VERSION 5.5 ;
NAMESCASESENSITIVE ON ;
BUSBITCHARS "[]" ;
DIVIDERCHAR "/" ;

PROPERTYDEFINITIONS
  LAYER routingPitch REAL ;
END PROPERTYDEFINITIONS

UNITS
  DATABASE MICRONS 1000 ;
END UNITS
MANUFACTURINGGRID 0.01 ;
LAYER POLY1
  TYPE MASTERSLICE ;
END POLY1

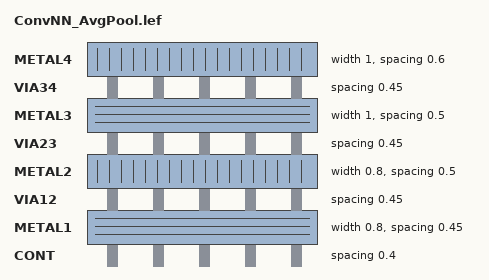
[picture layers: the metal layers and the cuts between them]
LAYER CONT
  TYPE CUT ;
  SPACING 0.4 ;
END CONT

LAYER METAL1
  TYPE ROUTING ;
  DIRECTION HORIZONTAL ;
  PITCH 0 ;
  WIDTH 0.8 ;
  SPACING 0.45 ;
  PROPERTY routingPitch 1.25 ;
END METAL1

LAYER VIA12
  TYPE CUT ;
  SPACING 0.45 ;
END VIA12

LAYER METAL2
  TYPE ROUTING ;
  DIRECTION VERTICAL ;
  PITCH 0 ;
  WIDTH 0.8 ;
  SPACING 0.5 ;
  PROPERTY routingPitch 1.4 ;
END METAL2

LAYER VIA23
  TYPE CUT ;
  SPACING 0.45 ;
END VIA23

LAYER METAL3
  TYPE ROUTING ;
  DIRECTION HORIZONTAL ;
  PITCH 0 ;
  WIDTH 1.0 ;
  SPACING 0.5 ;
  PROPERTY routingPitch 1.25 ;
END METAL3

LAYER VIA34
  TYPE CUT ;
  SPACING 0.45 ;
END VIA34

LAYER METAL4
  TYPE ROUTING ;
  DIRECTION VERTICAL ;
  PITCH 0 ;
  WIDTH 1.0 ;
  SPACING 0.6 ;
  PROPERTY routingPitch 1.4 ;
END METAL4

LAYER OVERLAP
  TYPE OVERLAP ;
END OVERLAP

VIARULE M4_M3 GENERATE
  LAYER METAL3 ;
    ENCLOSURE 0.2 0.2 ;
  LAYER METAL4 ;
    ENCLOSURE 0.15 0.15 ;
  LAYER VIA34 ;
    RECT -0.25 -0.25 0.25 0.25 ;
    SPACING 1 BY 1 ;
END M4_M3

VIARULE M3_M2 GENERATE
  LAYER METAL2 ;
    ENCLOSURE 0.2 0.2 ;
  LAYER METAL3 ;
    ENCLOSURE 0.15 0.15 ;
  LAYER VIA23 ;
    RECT -0.25 -0.25 0.25 0.25 ;
    SPACING 1 BY 1 ;
END M3_M2

VIARULE M2_M1 GENERATE
  LAYER METAL1 ;
    ENCLOSURE 0.2 0.2 ;
  LAYER METAL2 ;
    ENCLOSURE 0.15 0.15 ;
  LAYER VIA12 ;
    RECT -0.25 -0.25 0.25 0.25 ;
    SPACING 1 BY 1 ;
END M2_M1

VIARULE M1_POLY1 GENERATE
  LAYER POLY1 ;
    ENCLOSURE 0.2 0.2 ;
  LAYER METAL1 ;
    ENCLOSURE 0.15 0.15 ;
  LAYER CONT ;
    RECT -0.2 -0.2 0.2 0.2 ;
    SPACING 1 BY 1 ;
END M1_POLY1

VIA M1_POLY1
  LAYER CONT ;
    RECT -0.2 -0.2 0.2 0.2 ;
  LAYER POLY1 ;
    RECT -0.4 -0.4 0.4 0.4 ;
  LAYER METAL1 ;
    RECT -0.35 -0.35 0.35 0.35 ;
END M1_POLY1

VIA M2_M1
  LAYER VIA12 ;
    RECT -0.25 -0.25 0.25 0.25 ;
  LAYER METAL2 ;
    RECT -0.4 -0.4 0.4 0.4 ;
  LAYER METAL1 ;
    RECT -0.45 -0.45 0.45 0.45 ;
END M2_M1

VIA M3_M2
  LAYER VIA23 ;
    RECT -0.25 -0.25 0.25 0.25 ;
  LAYER METAL3 ;
    RECT -0.4 -0.4 0.4 0.4 ;
  LAYER METAL2 ;
    RECT -0.45 -0.45 0.45 0.45 ;
END M3_M2

VIA M4_M3
  LAYER VIA34 ;
    RECT -0.25 -0.25 0.25 0.25 ;
  LAYER METAL4 ;
    RECT -0.4 -0.4 0.4 0.4 ;
  LAYER METAL3 ;
    RECT -0.45 -0.45 0.45 0.45 ;
END M4_M3


MACRO TSMC350nm_VinjDecode2to4_vtile_spacing
END TSMC350nm_VinjDecode2to4_vtile_spacing

MACRO TSMC350nm_VinjDecode2to4_vtile_bridge_spacing
END TSMC350nm_VinjDecode2to4_vtile_bridge_spacing

MACRO TSMC350nm_VinjDecode2to4_vtile_D_bridge
END TSMC350nm_VinjDecode2to4_vtile_D_bridge

MACRO TSMC350nm_VinjDecode2to4_vtile
  PIN Vinj
    DIRECTION INOUT ;
    USE SIGNAL ;
    PORT
      LAYER METAL1 ;
        RECT 7.78 11.04 9.06 11.45 ;
    END
  END Vinj
  PIN OUT<0>
    DIRECTION INOUT ;
    USE SIGNAL ;
    PORT
      LAYER METAL1 ;
        RECT 19.66 18.91 20.11 19.59 ;
    END
  END OUT<0>
  PIN OUT<1>
    DIRECTION INOUT ;
    USE SIGNAL ;
    PORT
      LAYER METAL1 ;
        RECT 19.66 13.41 20.12 14.1 ;
    END
  END OUT<1>
  PIN OUT<2>
    DIRECTION INOUT ;
    USE SIGNAL ;
    PORT
      LAYER METAL1 ;
        RECT 19.66 7.92 20.11 8.59 ;
    END
  END OUT<2>
  PIN OUT<3>
    DIRECTION INOUT ;
    USE SIGNAL ;
    PORT
      LAYER METAL1 ;
        RECT 19.66 2.41 20.11 3.09 ;
    END
  END OUT<3>
  PIN ENABLE
    DIRECTION INOUT ;
    USE SIGNAL ;
    PORT
      LAYER METAL1 ;
        RECT 0.01 3.48 0.71 4.21 ;
    END
  END ENABLE
  PIN GND
    DIRECTION INOUT ;
    USE SIGNAL ;
    PORT
      LAYER METAL1 ;
        RECT 19.52 5.0 20.12 5.99 ;
    END
  END GND
  PIN VINJ
    DIRECTION INOUT ;
    USE SIGNAL ;
    PORT
      LAYER METAL1 ;
        RECT 19.15 21.56 20.05 21.96 ;
    END
  END VINJ
  PIN IN<1>
    DIRECTION INOUT ;
    USE SIGNAL ;
    PORT
      LAYER METAL2 ;
        RECT 6.56 20.89 7.5 22.0 ;
    END
  END IN<1>
  PIN IN<0>
    DIRECTION INOUT ;
    USE SIGNAL ;
    PORT
      LAYER METAL2 ;
        RECT 3.9 20.96 4.5 22.0 ;
    END
  END IN<0>
END TSMC350nm_VinjDecode2to4_vtile

MACRO TSMC350nm_VinjDecode2to4_vtile_C_bridge
END TSMC350nm_VinjDecode2to4_vtile_C_bridge

MACRO TSMC350nm_VinjDecode2to4_vtile_B_bridge
END TSMC350nm_VinjDecode2to4_vtile_B_bridge

MACRO TSMC350nm_VinjDecode2to4_vtile_A_bridge
END TSMC350nm_VinjDecode2to4_vtile_A_bridge

MACRO TSMC350nm_drainSelect_progrundrains
  PIN prog_drain<3>
    DIRECTION INOUT ;
    USE SIGNAL ;
    PORT
      LAYER METAL1 ;
        RECT 30.93 0.93 31.86 1.43 ;
    END
  END prog_drain<3>
  PIN prog_drain<2>
    DIRECTION INOUT ;
    USE SIGNAL ;
    PORT
      LAYER METAL1 ;
        RECT 30.97 9.62 31.86 10.12 ;
    END
  END prog_drain<2>
  PIN prog_drain<1>
    DIRECTION INOUT ;
    USE SIGNAL ;
    PORT
      LAYER METAL1 ;
        RECT 31.0 13.97 31.86 14.47 ;
    END
  END prog_drain<1>
  PIN run_drain<3>
    DIRECTION INOUT ;
    USE SIGNAL ;
    PORT
      LAYER METAL1 ;
        RECT 31.01 2.45 31.86 2.95 ;
    END
  END run_drain<3>
  PIN run_drain<2>
    DIRECTION INOUT ;
    USE SIGNAL ;
    PORT
      LAYER METAL1 ;
        RECT 30.94 5.31 31.86 5.81 ;
    END
  END run_drain<2>
  PIN prog_drain<0>
    DIRECTION INOUT ;
    USE SIGNAL ;
    PORT
      LAYER METAL1 ;
        RECT 31.12 20.75 31.86 21.25 ;
    END
  END prog_drain<0>
  PIN GND
    DIRECTION INOUT ;
    USE SIGNAL ;
    PORT
      LAYER METAL2 ;
        RECT 4.19 21.33 4.99 22.0 ;
    END
  END GND
  PIN VINJ
    DIRECTION INOUT ;
    USE SIGNAL ;
    PORT
      LAYER METAL1 ;
        RECT 1.4 21.5 2.8 22.0 ;
    END
  END VINJ
  PIN run_drain<0>
    DIRECTION INOUT ;
    USE SIGNAL ;
    PORT
      LAYER METAL1 ;
        RECT 31.01 19.56 31.86 20.06 ;
    END
  END run_drain<0>
  PIN run_drain<1>
    DIRECTION INOUT ;
    USE SIGNAL ;
    PORT
      LAYER METAL1 ;
        RECT 31.04 16.75 31.86 17.24 ;
    END
  END run_drain<1>
  PIN SELECT<3>
    DIRECTION INOUT ;
    USE SIGNAL ;
    PORT
      LAYER METAL1 ;
        RECT 0.0 2.54 0.67 2.97 ;
    END
  END SELECT<3>
  PIN SELET<2>
    DIRECTION INOUT ;
    USE SIGNAL ;
    PORT
      LAYER METAL1 ;
        RECT 0.0 8.03 0.67 8.46 ;
    END
  END SELET<2>
  PIN SELECT<1>
    DIRECTION INOUT ;
    USE SIGNAL ;
    PORT
      LAYER METAL1 ;
        RECT 0.0 13.54 0.67 13.97 ;
    END
  END SELECT<1>
  PIN SELECT<0>
    DIRECTION INOUT ;
    USE SIGNAL ;
    PORT
      LAYER METAL1 ;
        RECT 0.0 18.9 0.67 19.6 ;
    END
  END SELECT<0>
  PIN VINJ_b
    DIRECTION INOUT ;
    USE SIGNAL ;
    PORT
      LAYER METAL2 ;
        RECT 21.94 0.0 23.29 0.58 ;
    END
  END VINJ_b
  PIN GND_b
    DIRECTION INOUT ;
    USE SIGNAL ;
    PORT
      LAYER METAL2 ;
        RECT 17.16 0.0 18.16 0.58 ;
    END
  END GND_b
  PIN run_drainrail
    DIRECTION INOUT ;
    USE SIGNAL ;
    PORT
      LAYER METAL2 ;
        RECT 27.01 21.19 27.71 22.0 ;
    END
  END run_drainrail
  PIN prog_drainrail
    DIRECTION INOUT ;
    USE SIGNAL ;
    PORT
      LAYER METAL2 ;
        RECT 7.36 21.34 8.16 22.0 ;
    END
  END prog_drainrail
END TSMC350nm_drainSelect_progrundrains

MACRO TSMC350nm_4TGate_ST_draincutoff
  PIN In<0>
    DIRECTION INOUT ;
    USE SIGNAL ;
    PORT
      LAYER METAL1 ;
        RECT 9.96 17.5 10.6 18.45 ;
    END
  END In<0>
  PIN In<1>
    DIRECTION INOUT ;
    USE SIGNAL ;
    PORT
      LAYER METAL1 ;
        RECT 9.91 14.7 10.6 15.93 ;
    END
  END In<1>
  PIN In<2>
    DIRECTION INOUT ;
    USE SIGNAL ;
    PORT
      LAYER METAL1 ;
        RECT 10.01 6.9 10.6 7.8 ;
    END
  END In<2>
  PIN In<3>
    DIRECTION INOUT ;
    USE SIGNAL ;
    PORT
      LAYER METAL1 ;
        RECT 10.02 3.5 10.6 4.3 ;
    END
  END In<3>
  PIN A<0>
    DIRECTION INOUT ;
    USE SIGNAL ;
    PORT
      LAYER METAL1 ;
        RECT 0.0 19.56 1.4 20.06 ;
    END
  END A<0>
  PIN A<1>
    DIRECTION INOUT ;
    USE SIGNAL ;
    PORT
      LAYER METAL1 ;
        RECT 0.0 16.75 1.4 17.25 ;
    END
  END A<1>
  PIN A<2>
    DIRECTION INOUT ;
    USE SIGNAL ;
    PORT
      LAYER METAL1 ;
        RECT 0.0 5.3 1.4 5.8 ;
    END
  END A<2>
  PIN A<3>
    DIRECTION INOUT ;
    USE SIGNAL ;
    PORT
      LAYER METAL1 ;
        RECT 0.0 2.45 1.4 2.95 ;
    END
  END A<3>
  PIN P<0>
    DIRECTION INOUT ;
    USE SIGNAL ;
    PORT
      LAYER METAL1 ;
        RECT 0.0 20.75 1.4 21.25 ;
    END
  END P<0>
  PIN P<1>
    DIRECTION INOUT ;
    USE SIGNAL ;
    PORT
      LAYER METAL1 ;
        RECT 0.0 13.97 1.4 14.47 ;
    END
  END P<1>
  PIN P<2>
    DIRECTION INOUT ;
    USE SIGNAL ;
    PORT
      LAYER METAL1 ;
        RECT 0.0 9.62 1.4 10.12 ;
    END
  END P<2>
  PIN P<3>
    DIRECTION INOUT ;
    USE SIGNAL ;
    PORT
      LAYER METAL1 ;
        RECT 0.0 0.93 1.4 1.43 ;
    END
  END P<3>
  PIN PR<0>
    DIRECTION INOUT ;
    USE SIGNAL ;
    PORT
      LAYER METAL1 ;
        RECT 10.0 20.3 10.6 21.25 ;
    END
  END PR<0>
  PIN PR<1>
    DIRECTION INOUT ;
    USE SIGNAL ;
    PORT
      LAYER METAL1 ;
        RECT 10.13 11.9 10.6 12.8 ;
    END
  END PR<1>
  PIN PR<2>
    DIRECTION INOUT ;
    USE SIGNAL ;
    PORT
      LAYER METAL1 ;
        RECT 10.0 9.4 10.6 10.3 ;
    END
  END PR<2>
  PIN PR<3>
    DIRECTION INOUT ;
    USE SIGNAL ;
    PORT
      LAYER METAL1 ;
        RECT 10.0 0.7 10.6 1.6 ;
    END
  END PR<3>
  PIN VDD_b
    DIRECTION INOUT ;
    USE SIGNAL ;
    PORT
      LAYER METAL2 ;
        RECT 7.89 0.0 8.79 0.54 ;
    END
  END VDD_b
  PIN RUN
    DIRECTION INOUT ;
    USE SIGNAL ;
    PORT
      LAYER METAL2 ;
        RECT 5.9 21.13 6.5 22.0 ;
    END
  END RUN
  PIN VDD
    DIRECTION INOUT ;
    USE SIGNAL ;
    PORT
      LAYER METAL2 ;
        RECT 7.89 21.3 8.79 22.0 ;
    END
  END VDD
  PIN GND
    DIRECTION INOUT ;
    USE SIGNAL ;
    PORT
      LAYER METAL2 ;
        RECT 3.35 21.3 4.25 22.0 ;
    END
  END GND
  PIN GND_b
    DIRECTION INOUT ;
    USE SIGNAL ;
    PORT
      LAYER METAL2 ;
        RECT 3.35 0.0 4.25 0.73 ;
    END
  END GND_b
  PIN RUN_b
    DIRECTION INOUT ;
    USE SIGNAL ;
    PORT
      LAYER METAL2 ;
        RECT 5.9 0.0 6.5 0.71 ;
    END
  END RUN_b
END TSMC350nm_4TGate_ST_draincutoff

MACRO TSMC350nm_IndirectSwitches
  PIN GND_B<1>
    DIRECTION INOUT ;
    USE SIGNAL ;
    PORT
      LAYER METAL2 ;
        RECT 15.41 0.0 16.01 0.85 ;
    END
  END GND_B<1>
  PIN GND_B<0>
    DIRECTION INOUT ;
    USE SIGNAL ;
    PORT
      LAYER METAL2 ;
        RECT 11.2 0.0 11.8 0.85 ;
    END
  END GND_B<0>
  PIN GND
    DIRECTION INOUT ;
    USE SIGNAL ;
    PORT
      LAYER METAL2 ;
        RECT 11.2 3.21 11.8 3.6 ;
    END
  END GND
  PIN GND_T
    DIRECTION INOUT ;
    USE SIGNAL ;
    PORT
      LAYER METAL2 ;
        RECT 15.4 21.0 16.2 22.0 ;
    END
  END GND_T
  PIN VINJ_T
    DIRECTION INOUT ;
    USE SIGNAL ;
    PORT
      LAYER METAL2 ;
        RECT 6.3 21.04 7.32 22.0 ;
    END
  END VINJ_T
  PIN VDD<1>
    DIRECTION INOUT ;
    USE SIGNAL ;
    PORT
      LAYER METAL2 ;
        RECT 24.5 0.0 25.1 0.75 ;
    END
  END VDD<1>
  PIN VTUN
    DIRECTION INOUT ;
    USE SIGNAL ;
    PORT
      LAYER METAL2 ;
        RECT 13.3 0.0 13.9 0.82 ;
    END
  END VTUN
  PIN VINJ
    DIRECTION INOUT ;
    USE SIGNAL ;
    PORT
      LAYER METAL2 ;
        RECT 4.2 0.0 4.8 1.0 ;
    END
  END VINJ
  PIN VDD<0>
    DIRECTION INOUT ;
    USE SIGNAL ;
    PORT
      LAYER METAL2 ;
        RECT 2.1 0.0 2.7 1.09 ;
    END
  END VDD<0>
  PIN Vg<0>
    DIRECTION INOUT ;
    USE SIGNAL ;
    PORT
      LAYER METAL2 ;
        RECT 8.4 0.005 9.0 0.825 ;
    END
  END Vg<0>
  PIN CTRL_B<0>
    DIRECTION INOUT ;
    USE SIGNAL ;
    PORT
      LAYER METAL2 ;
        RECT 6.3 0.01 6.9 0.76 ;
    END
  END CTRL_B<0>
  PIN CTRL_B<1>
    DIRECTION INOUT ;
    USE SIGNAL ;
    PORT
      LAYER METAL2 ;
        RECT 20.3 0.01 20.9 0.75 ;
    END
  END CTRL_B<1>
  PIN Vg<1>
    DIRECTION INOUT ;
    USE SIGNAL ;
    PORT
      LAYER METAL2 ;
        RECT 18.2 0.0 18.8 0.76 ;
    END
  END Vg<1>
  PIN decode<0>
    DIRECTION INOUT ;
    USE SIGNAL ;
    PORT
      LAYER METAL2 ;
        RECT 3.46 21.16 4.8 22.0 ;
    END
  END decode<0>
  PIN RUN_IN<1>
    DIRECTION INOUT ;
    USE SIGNAL ;
    PORT
      LAYER METAL2 ;
        RECT 17.5 21.01 18.1 22.0 ;
    END
  END RUN_IN<1>
  PIN RUN_IN<0>
    DIRECTION INOUT ;
    USE SIGNAL ;
    PORT
      LAYER METAL2 ;
        RECT 10.5 20.9 11.1 22.0 ;
    END
  END RUN_IN<0>
  PIN VPWR<1>
    DIRECTION INOUT ;
    USE SIGNAL ;
    PORT
      LAYER METAL2 ;
        RECT 21.7 21.08 22.3 22.0 ;
    END
  END VPWR<1>
  PIN decode<1>
    DIRECTION INOUT ;
    USE SIGNAL ;
    PORT
      LAYER METAL2 ;
        RECT 23.8 21.09 25.0 22.0 ;
    END
  END decode<1>
  PIN VPWR<0>
    DIRECTION INOUT ;
    USE SIGNAL ;
    PORT
      LAYER METAL2 ;
        RECT 1.71 21.21 2.43 22.0 ;
    END
  END VPWR<0>
  PIN VTUN_T
    DIRECTION INOUT ;
    USE SIGNAL ;
    PORT
      LAYER METAL2 ;
        RECT 12.6 21.12 13.7 22.0 ;
    END
  END VTUN_T
  PIN vtun_r
    DIRECTION INOUT ;
    USE SIGNAL ;
    PORT
      LAYER METAL1 ;
        RECT 26.17 0.9 27.46 2.17 ;
    END
  END vtun_r
  PIN vgsel_r
    DIRECTION INOUT ;
    USE SIGNAL ;
    PORT
      LAYER METAL1 ;
        RECT 26.52 3.15 27.46 4.45 ;
    END
  END vgsel_r
  PIN prog_r
    DIRECTION INOUT ;
    USE SIGNAL ;
    PORT
      LAYER METAL1 ;
        RECT 26.59 9.15 27.46 10.55 ;
    END
  END prog_r
  PIN run_r
    DIRECTION INOUT ;
    USE SIGNAL ;
    PORT
      LAYER METAL1 ;
        RECT 26.28 6.05 27.46 7.29 ;
    END
  END run_r
  PIN RUN
    DIRECTION INOUT ;
    USE SIGNAL ;
    PORT
      LAYER METAL1 ;
        RECT 0.0 6.05 0.91 7.29 ;
    END
  END RUN
  PIN PROG
    DIRECTION INOUT ;
    USE SIGNAL ;
    PORT
      LAYER METAL1 ;
        RECT 0.0 9.15 0.87 10.55 ;
    END
  END PROG
  PIN Vgsel
    DIRECTION INOUT ;
    USE SIGNAL ;
    PORT
      LAYER METAL1 ;
        RECT 0.0 3.72 0.91 4.45 ;
    END
  END Vgsel
  PIN vtun_l
    DIRECTION INOUT ;
    USE SIGNAL ;
    PORT
      LAYER METAL1 ;
        RECT 0.0 0.9 1.31 1.88 ;
    END
  END vtun_l
END TSMC350nm_IndirectSwitches

MACRO TSMC350nm_VinjDecode2to4_htile
  PIN IN<1>
    DIRECTION INOUT ;
    USE SIGNAL ;
    PORT
      LAYER METAL1 ;
        RECT 0.0 11.85 0.9 12.74 ;
    END
  END IN<1>
  PIN IN<0>
    DIRECTION INOUT ;
    USE SIGNAL ;
    PORT
      LAYER METAL1 ;
        RECT 0.0 10.13 0.87 11.1 ;
    END
  END IN<0>
  PIN VINJ
    DIRECTION INOUT ;
    USE SIGNAL ;
    PORT
      LAYER METAL1 ;
        RECT 0.0 1.99 0.5 2.49 ;
    END
  END VINJ
  PIN GND
    DIRECTION INOUT ;
    USE SIGNAL ;
    PORT
      LAYER METAL1 ;
        RECT 0.0 6.99 0.51 7.49 ;
    END
  END GND
  PIN GND_b<1>
    DIRECTION INOUT ;
    USE SIGNAL ;
    PORT
      LAYER METAL2 ;
        RECT 40.32 0.0 40.92 1.79 ;
    END
  END GND_b<1>
  PIN VINJ_b<1>
    DIRECTION INOUT ;
    USE SIGNAL ;
    PORT
      LAYER METAL2 ;
        RECT 22.1 0.0 22.7 1.44 ;
    END
  END VINJ_b<1>
  PIN GND_b<0>
    DIRECTION INOUT ;
    USE SIGNAL ;
    PORT
      LAYER METAL2 ;
        RECT 18.85 0.0 19.45 1.41 ;
    END
  END GND_b<0>
  PIN VINJ_b<0>
    DIRECTION INOUT ;
    USE SIGNAL ;
    PORT
      LAYER METAL2 ;
        RECT 1.07 0.0 1.67 1.25 ;
    END
  END VINJ_b<0>
  PIN VINJV
    DIRECTION INOUT ;
    USE SIGNAL ;
    PORT
      LAYER METAL2 ;
        RECT 23.7 21.26 24.31 22.0 ;
    END
  END VINJV
  PIN GNDV
    DIRECTION INOUT ;
    USE SIGNAL ;
    PORT
      LAYER METAL2 ;
        RECT 25.84 21.28 26.44 22.0 ;
    END
  END GNDV
  PIN RUN_OUT<3>
    DIRECTION INOUT ;
    USE SIGNAL ;
    PORT
      LAYER METAL2 ;
        RECT 34.39 0.0 35.19 0.86 ;
    END
  END RUN_OUT<3>
  PIN RUN_OUT<2>
    DIRECTION INOUT ;
    USE SIGNAL ;
    PORT
      LAYER METAL2 ;
        RECT 28.77 0.0 29.57 0.86 ;
    END
  END RUN_OUT<2>
  PIN RUN_OUT<1>
    DIRECTION INOUT ;
    USE SIGNAL ;
    PORT
      LAYER METAL2 ;
        RECT 13.5 0.0 14.1 0.86 ;
    END
  END RUN_OUT<1>
  PIN RUN_OUT<0>
    DIRECTION INOUT ;
    USE SIGNAL ;
    PORT
      LAYER METAL2 ;
        RECT 7.34 0.0 8.14 0.86 ;
    END
  END RUN_OUT<0>
  PIN ENABLE
    DIRECTION INOUT ;
    USE SIGNAL ;
    PORT
      LAYER METAL2 ;
        RECT 6.29 21.66 6.89 22.0 ;
    END
  END ENABLE
  PIN OUT<2>
    DIRECTION INOUT ;
    USE SIGNAL ;
    PORT
      LAYER METAL2 ;
        RECT 25.28 0.0 25.87 0.87 ;
    END
  END OUT<2>
  PIN OUT<3>
    DIRECTION INOUT ;
    USE SIGNAL ;
    PORT
      LAYER METAL2 ;
        RECT 37.14 0.0 37.73 0.83 ;
    END
  END OUT<3>
  PIN OUT<0>
    DIRECTION INOUT ;
    USE SIGNAL ;
    PORT
      LAYER METAL2 ;
        RECT 4.27 0.0 4.87 0.86 ;
    END
  END OUT<0>
  PIN OUT<1>
    DIRECTION INOUT ;
    USE SIGNAL ;
    PORT
      LAYER METAL2 ;
        RECT 16.14 0.0 16.72 0.85 ;
    END
  END OUT<1>
  PIN VGRUN<0>
    DIRECTION INOUT ;
    USE SIGNAL ;
    PORT
      LAYER METAL2 ;
        RECT 9.1 21.59 9.7 22.0 ;
    END
  END VGRUN<0>
  PIN VGRUN<1>
    DIRECTION INOUT ;
    USE SIGNAL ;
    PORT
      LAYER METAL2 ;
        RECT 11.2 21.6 11.8 22.0 ;
    END
  END VGRUN<1>
  PIN VGRUN<2>
    DIRECTION INOUT ;
    USE SIGNAL ;
    PORT
      LAYER METAL2 ;
        RECT 28.7 21.71 29.3 22.0 ;
    END
  END VGRUN<2>
  PIN VGRUN<3>
    DIRECTION INOUT ;
    USE SIGNAL ;
    PORT
      LAYER METAL2 ;
        RECT 33.6 21.54 34.2 22.0 ;
    END
  END VGRUN<3>
END TSMC350nm_VinjDecode2to4_htile

MACRO TSMC350nm_VinjDecode2to4_htile_A_bridge
  PIN VGRUN<3>
    DIRECTION INOUT ;
    USE SIGNAL ;
    PORT
      LAYER METAL2 ;
        RECT 34.5 9.46 35.1 10.0 ;
    END
  END VGRUN<3>
  PIN VGRUN<2>
    DIRECTION INOUT ;
    USE SIGNAL ;
    PORT
      LAYER METAL2 ;
        RECT 26.6 9.56 27.2 10.0 ;
    END
  END VGRUN<2>
  PIN VGRUN<1>
    DIRECTION INOUT ;
    USE SIGNAL ;
    PORT
      LAYER METAL2 ;
        RECT 13.5 9.46 14.1 10.0 ;
    END
  END VGRUN<1>
  PIN VGRUN<0>
    DIRECTION INOUT ;
    USE SIGNAL ;
    PORT
      LAYER METAL2 ;
        RECT 5.6 9.52 6.2 10.0 ;
    END
  END VGRUN<0>
END TSMC350nm_VinjDecode2to4_htile_A_bridge

MACRO TSMC350nm_VinjDecode2to4_htile_B_bridge
  PIN VGRUN<0>
    DIRECTION INOUT ;
    USE SIGNAL ;
    PORT
      LAYER METAL2 ;
        RECT 9.1 9.52 9.7 10.0 ;
    END
  END VGRUN<0>
  PIN VGRUN<1>
    DIRECTION INOUT ;
    USE SIGNAL ;
    PORT
      LAYER METAL2 ;
        RECT 11.2 9.52 11.8 10.0 ;
    END
  END VGRUN<1>
  PIN VGRUN<2>
    DIRECTION INOUT ;
    USE SIGNAL ;
    PORT
      LAYER METAL2 ;
        RECT 28.7 9.5 29.3 10.0 ;
    END
  END VGRUN<2>
  PIN VGRUN<3>
    DIRECTION INOUT ;
    USE SIGNAL ;
    PORT
      LAYER METAL2 ;
        RECT 33.6 9.51 34.2 10.0 ;
    END
  END VGRUN<3>
END TSMC350nm_VinjDecode2to4_htile_B_bridge

MACRO TSMC350nm_VinjDecode2to4_htile_C_bridge
  PIN VGRUN<0>
    DIRECTION INOUT ;
    USE SIGNAL ;
    PORT
      LAYER METAL2 ;
        RECT 9.1 9.54 9.7 10.0 ;
    END
  END VGRUN<0>
  PIN VGRUN<1>
    DIRECTION INOUT ;
    USE SIGNAL ;
    PORT
      LAYER METAL2 ;
        RECT 11.2 9.57 11.8 10.0 ;
    END
  END VGRUN<1>
  PIN VGRUN<2>
    DIRECTION INOUT ;
    USE SIGNAL ;
    PORT
      LAYER METAL2 ;
        RECT 28.7 9.59 29.3 10.0 ;
    END
  END VGRUN<2>
  PIN VGRUN<3>
    DIRECTION INOUT ;
    USE SIGNAL ;
    PORT
      LAYER METAL2 ;
        RECT 33.6 9.57 34.2 10.0 ;
    END
  END VGRUN<3>
END TSMC350nm_VinjDecode2to4_htile_C_bridge

MACRO TSMC350nm_VinjDecode2to4_htile_spacing
  PIN VGRUN<0>
    DIRECTION INOUT ;
    USE SIGNAL ;
    PORT
      LAYER METAL2 ;
        RECT 9.1 21.59 9.7 22.0 ;
    END
  END VGRUN<0>
  PIN VGRUN<1>
    DIRECTION INOUT ;
    USE SIGNAL ;
    PORT
      LAYER METAL2 ;
        RECT 11.2 21.52 11.8 22.0 ;
    END
  END VGRUN<1>
  PIN VGRUN<2>
    DIRECTION INOUT ;
    USE SIGNAL ;
    PORT
      LAYER METAL2 ;
        RECT 28.7 21.54 29.3 22.0 ;
    END
  END VGRUN<2>
  PIN VGRUN<3>
    DIRECTION INOUT ;
    USE SIGNAL ;
    PORT
      LAYER METAL2 ;
        RECT 33.6 21.55 34.2 22.0 ;
    END
  END VGRUN<3>
END TSMC350nm_VinjDecode2to4_htile_spacing

MACRO Tgate_swc_fr_Kernel_Vert
  PIN Vimg
    DIRECTION INOUT ;
    USE SIGNAL ;
    PORT
      LAYER METAL1 ;
        RECT 0.0 17.02 0.39 17.72 ;
    END
  END Vimg
  PIN AVDD
    DIRECTION INOUT ;
    USE SIGNAL ;
    PORT
      LAYER METAL1 ;
        RECT 0.0 14.02 0.39 15.02 ;
    END
  END AVDD
  PIN DVDD
    DIRECTION INOUT ;
    USE SIGNAL ;
    PORT
      LAYER METAL1 ;
        RECT 0.0 9.47 0.39 10.47 ;
    END
  END DVDD
  PIN GND
    DIRECTION INOUT ;
    USE SIGNAL ;
    PORT
      LAYER METAL2 ;
        RECT 4.39 21.77 5.19 22.0 ;
    END
  END GND
  PIN Q_bot
    DIRECTION INOUT ;
    USE SIGNAL ;
    PORT
      LAYER METAL2 ;
        RECT 6.57 0.0 7.35 0.35 ;
    END
  END Q_bot
  PIN Vg_R
    DIRECTION INOUT ;
    USE SIGNAL ;
    PORT
      LAYER METAL2 ;
        RECT 1.25 0.0 2.05 0.35 ;
    END
  END Vg_R
  PIN Q
    DIRECTION INOUT ;
    USE SIGNAL ;
    PORT
      LAYER METAL2 ;
        RECT 8.6 21.77 9.2 22.0 ;
    END
  END Q
END Tgate_swc_fr_Kernel_Vert

MACRO DynamicShiftReg_Rst_Lo
  PIN Q
    DIRECTION INOUT ;
    USE SIGNAL ;
    PORT
      LAYER METAL1 ;
        RECT 10.73 19.48 11.13 20.18 ;
    END
  END Q
  PIN GND
    DIRECTION INOUT ;
    USE SIGNAL ;
    PORT
      LAYER METAL1 ;
        RECT 0.0 0.5 0.4 1.3 ;
    END
  END GND
  PIN Din
    DIRECTION INOUT ;
    USE SIGNAL ;
    PORT
      LAYER METAL1 ;
        RECT 0.0 19.48 0.4 20.18 ;
    END
  END Din
  PIN RST
    DIRECTION INOUT ;
    USE SIGNAL ;
    PORT
      LAYER METAL1 ;
        RECT 0.0 10.56 0.4 11.26 ;
    END
  END RST
  PIN DVDD
    DIRECTION INOUT ;
    USE SIGNAL ;
    PORT
      LAYER METAL1 ;
        RECT 0.0 13.07 0.4 13.77 ;
    END
  END DVDD
  PIN CLK
    DIRECTION INOUT ;
    USE SIGNAL ;
    PORT
      LAYER METAL1 ;
        RECT 0.0 9.15 0.4 9.85 ;
    END
  END CLK
  PIN CLKB
    DIRECTION INOUT ;
    USE SIGNAL ;
    PORT
      LAYER METAL1 ;
        RECT 0.0 7.92 0.4 8.62 ;
    END
  END CLKB
END DynamicShiftReg_Rst_Lo

MACRO Integration_fr_AvgPool_core
  PIN GND
    DIRECTION INOUT ;
    USE SIGNAL ;
    PORT
      LAYER METAL1 ;
        RECT 71.84 21.51 73.23 22.0 ;
    END
  END GND
  PIN Q
    DIRECTION INOUT ;
    USE SIGNAL ;
    PORT
      LAYER METAL3 ;
        RECT 0.0 6.24 0.6 7.04 ;
    END
  END Q
  PIN Vd_run
    DIRECTION INOUT ;
    USE SIGNAL ;
    PORT
      LAYER METAL2 ;
        RECT 0.0 16.45 0.37 17.25 ;
    END
  END Vd_run
  PIN Vd_prog
    DIRECTION INOUT ;
    USE SIGNAL ;
    PORT
      LAYER METAL2 ;
        RECT 0.0 20.43 0.37 21.23 ;
    END
  END Vd_prog
  PIN int_rst
    DIRECTION INOUT ;
    USE SIGNAL ;
    PORT
      LAYER METAL2 ;
        RECT 0.0 13.45 0.37 14.25 ;
    END
  END int_rst
  PIN Vint
    DIRECTION INOUT ;
    USE SIGNAL ;
    PORT
      LAYER METAL2 ;
        RECT 0.0 14.95 0.37 15.75 ;
    END
  END Vint
  PIN DVDD
    DIRECTION INOUT ;
    USE SIGNAL ;
    PORT
      LAYER METAL2 ;
        RECT 0.0 11.95 0.37 12.75 ;
    END
  END DVDD
  PIN Din
    DIRECTION INOUT ;
    USE SIGNAL ;
    PORT
      LAYER METAL3 ;
        RECT 0.0 2.15 0.6 2.95 ;
    END
  END Din
  PIN RST_B
    DIRECTION INOUT ;
    USE SIGNAL ;
    PORT
      LAYER METAL1 ;
        RECT 14.55 21.51 15.35 22.0 ;
    END
  END RST_B
  PIN CLK
    DIRECTION INOUT ;
    USE SIGNAL ;
    PORT
      LAYER METAL1 ;
        RECT 13.14 21.51 14.1 22.0 ;
    END
  END CLK
  PIN Vimg_CLK
    DIRECTION INOUT ;
    USE SIGNAL ;
    PORT
      LAYER METAL1 ;
        RECT 27.28 21.51 28.28 22.0 ;
    END
  END Vimg_CLK
  PIN CLKB
    DIRECTION INOUT ;
    USE SIGNAL ;
    PORT
      LAYER METAL1 ;
        RECT 11.61 21.51 12.61 22.0 ;
    END
  END CLKB
  PIN nxt_row<1>
    DIRECTION INOUT ;
    USE SIGNAL ;
    PORT
      LAYER METAL1 ;
        RECT 290.26 21.52 291.26 22.0 ;
    END
  END nxt_row<1>
  PIN AVDD_by_2<1>
    DIRECTION INOUT ;
    USE SIGNAL ;
    PORT
      LAYER METAL1 ;
        RECT 197.65 21.52 198.65 22.0 ;
    END
  END AVDD_by_2<1>
  PIN prog<1>
    DIRECTION INOUT ;
    USE SIGNAL ;
    PORT
      LAYER METAL1 ;
        RECT 195.23 21.52 196.23 22.0 ;
    END
  END prog<1>
  PIN run<1>
    DIRECTION INOUT ;
    USE SIGNAL ;
    PORT
      LAYER METAL1 ;
        RECT 192.83 21.52 193.83 22.0 ;
    END
  END run<1>
  PIN Vg<1>
    DIRECTION INOUT ;
    USE SIGNAL ;
    PORT
      LAYER METAL1 ;
        RECT 190.43 21.52 191.43 22.0 ;
    END
  END Vg<1>
  PIN Vsel_b<1>
    DIRECTION INOUT ;
    USE SIGNAL ;
    PORT
      LAYER METAL1 ;
        RECT 187.93 21.51 188.93 22.0 ;
    END
  END Vsel_b<1>
  PIN AVDD<1>
    DIRECTION INOUT ;
    USE SIGNAL ;
    PORT
      LAYER METAL1 ;
        RECT 185.43 21.51 186.43 22.0 ;
    END
  END AVDD<1>
  PIN VINJ<1>
    DIRECTION INOUT ;
    USE SIGNAL ;
    PORT
      LAYER METAL1 ;
        RECT 176.82 21.51 177.82 22.0 ;
    END
  END VINJ<1>
  PIN VTUN
    DIRECTION INOUT ;
    USE SIGNAL ;
    PORT
      LAYER METAL1 ;
        RECT 167.86 21.51 168.86 22.0 ;
    END
  END VTUN
  PIN VINJ<0>
    DIRECTION INOUT ;
    USE SIGNAL ;
    PORT
      LAYER METAL1 ;
        RECT 158.92 21.51 159.92 22.0 ;
    END
  END VINJ<0>
  PIN AVDD<0>
    DIRECTION INOUT ;
    USE SIGNAL ;
    PORT
      LAYER METAL1 ;
        RECT 150.82 21.51 151.82 22.0 ;
    END
  END AVDD<0>
  PIN Vsel_b<0>
    DIRECTION INOUT ;
    USE SIGNAL ;
    PORT
      LAYER METAL1 ;
        RECT 148.32 21.51 149.32 22.0 ;
    END
  END Vsel_b<0>
  PIN Vg<0>
    DIRECTION INOUT ;
    USE SIGNAL ;
    PORT
      LAYER METAL1 ;
        RECT 145.82 21.51 146.82 22.0 ;
    END
  END Vg<0>
  PIN run<0>
    DIRECTION INOUT ;
    USE SIGNAL ;
    PORT
      LAYER METAL1 ;
        RECT 143.42 21.51 144.42 22.0 ;
    END
  END run<0>
  PIN prog<0>
    DIRECTION INOUT ;
    USE SIGNAL ;
    PORT
      LAYER METAL1 ;
        RECT 141.02 21.51 142.02 22.0 ;
    END
  END prog<0>
  PIN AVDD_by_2<0>
    DIRECTION INOUT ;
    USE SIGNAL ;
    PORT
      LAYER METAL1 ;
        RECT 138.6 21.51 139.6 22.0 ;
    END
  END AVDD_by_2<0>
  PIN nxt_row<0>
    DIRECTION INOUT ;
    USE SIGNAL ;
    PORT
      LAYER METAL1 ;
        RECT 45.99 21.51 46.99 22.0 ;
    END
  END nxt_row<0>
END Integration_fr_AvgPool_core

MACRO I_Subtractor_AvgPool_core
  PIN Vd_prog_0_in
    DIRECTION INOUT ;
    USE SIGNAL ;
    PORT
      LAYER METAL2 ;
        RECT 0.0 18.88 0.37 19.88 ;
    END
  END Vd_prog_0_in
  PIN Vd_prog_0_out
    DIRECTION INOUT ;
    USE SIGNAL ;
    PORT
      LAYER METAL2 ;
        RECT 38.54 20.43 38.91 21.23 ;
    END
  END Vd_prog_0_out
  PIN Vd_run_krnl
    DIRECTION INOUT ;
    USE SIGNAL ;
    PORT
      LAYER METAL2 ;
        RECT 0.0 5.66 0.37 6.66 ;
    END
  END Vd_run_krnl
  PIN Vd_run_avg_pool
    DIRECTION INOUT ;
    USE SIGNAL ;
    PORT
      LAYER METAL2 ;
        RECT 38.54 16.45 38.91 17.25 ;
    END
  END Vd_run_avg_pool
  PIN Vint_out
    DIRECTION INOUT ;
    USE SIGNAL ;
    PORT
      LAYER METAL2 ;
        RECT 38.54 14.95 38.91 15.75 ;
    END
  END Vint_out
  PIN DVDD
    DIRECTION INOUT ;
    USE SIGNAL ;
    PORT
      LAYER METAL1 ;
        RECT 31.8 21.54 32.8 22.0 ;
    END
  END DVDD
  PIN GND
    DIRECTION INOUT ;
    USE SIGNAL ;
    PORT
      LAYER METAL1 ;
        RECT 12.02 21.54 17.24 22.0 ;
    END
  END GND
  PIN Vint_in
    DIRECTION INOUT ;
    USE SIGNAL ;
    PORT
      LAYER METAL2 ;
        RECT 0.0 16.27 0.37 17.27 ;
    END
  END Vint_in
  PIN run_lv
    DIRECTION INOUT ;
    USE SIGNAL ;
    PORT
      LAYER METAL1 ;
        RECT 36.65 21.54 37.65 22.0 ;
    END
  END run_lv
  PIN prog_lv
    DIRECTION INOUT ;
    USE SIGNAL ;
    PORT
      LAYER METAL1 ;
        RECT 29.8 21.54 30.8 22.0 ;
    END
  END prog_lv
END I_Subtractor_AvgPool_core

MACRO Tgate_swc_fr_Kernel_Horiz_top_edge
  PIN Q
    DIRECTION INOUT ;
    USE SIGNAL ;
    PORT
      LAYER METAL1 ;
        RECT 10.73 19.48 11.13 20.18 ;
    END
  END Q
  PIN GND
    DIRECTION INOUT ;
    USE SIGNAL ;
    PORT
      LAYER METAL1 ;
        RECT 30.84 21.37 31.64 22.0 ;
    END
  END GND
  PIN Din
    DIRECTION INOUT ;
    USE SIGNAL ;
    PORT
      LAYER METAL1 ;
        RECT 49.82 21.37 50.52 22.0 ;
    END
  END Din
  PIN RST
    DIRECTION INOUT ;
    USE SIGNAL ;
    PORT
      LAYER METAL1 ;
        RECT 0.0 10.56 0.4 11.26 ;
    END
  END RST
  PIN DVDD
    DIRECTION INOUT ;
    USE SIGNAL ;
    PORT
      LAYER METAL1 ;
        RECT 43.41 21.37 44.11 22.0 ;
    END
  END DVDD
  PIN CLK
    DIRECTION INOUT ;
    USE SIGNAL ;
    PORT
      LAYER METAL1 ;
        RECT 39.49 21.37 40.19 22.0 ;
    END
  END CLK
  PIN CLKB
    DIRECTION INOUT ;
    USE SIGNAL ;
    PORT
      LAYER METAL1 ;
        RECT 38.26 21.37 38.96 22.0 ;
    END
  END CLKB
  PIN Final_row_out
    DIRECTION INOUT ;
    USE SIGNAL ;
    PORT
      LAYER METAL1 ;
        RECT 52.52 21.4 53.32 22.0 ;
    END
  END Final_row_out
  PIN I_m
    DIRECTION INOUT ;
    USE SIGNAL ;
    PORT
      LAYER METAL2 ;
        RECT 53.79 12.7 54.46 13.7 ;
    END
  END I_m
  PIN I_p
    DIRECTION INOUT ;
    USE SIGNAL ;
    PORT
      LAYER METAL2 ;
        RECT 53.79 16.27 54.46 17.27 ;
    END
  END I_p
  PIN Vd<0>
    DIRECTION INOUT ;
    USE SIGNAL ;
    PORT
      LAYER METAL1 ;
        RECT 0.0 17.5 0.42 18.2 ;
    END
  END Vd<0>
  PIN RUN_HV
    DIRECTION INOUT ;
    USE SIGNAL ;
    PORT
      LAYER METAL2 ;
        RECT 23.12 21.33 23.92 22.0 ;
    END
  END RUN_HV
  PIN VINJ
    DIRECTION INOUT ;
    USE SIGNAL ;
    PORT
      LAYER METAL2 ;
        RECT 9.08 21.33 10.08 22.0 ;
    END
  END VINJ
  PIN Vd_prog_0_out
    DIRECTION INOUT ;
    USE SIGNAL ;
    PORT
      LAYER METAL2 ;
        RECT 53.79 18.87 54.46 19.87 ;
    END
  END Vd_prog_0_out
  PIN Final_row_in
    DIRECTION INOUT ;
    USE SIGNAL ;
    PORT
      LAYER METAL1 ;
        RECT 52.52 0.0 53.32 0.6 ;
    END
  END Final_row_in
  PIN Vd_prog_0_in
    DIRECTION INOUT ;
    USE SIGNAL ;
    PORT
      LAYER METAL1 ;
        RECT 0.0 20.3 0.41 20.8 ;
    END
  END Vd_prog_0_in
  PIN Q<1>
    DIRECTION INOUT ;
    USE SIGNAL ;
    PORT
      LAYER METAL1 ;
        RECT 49.82 0.0 50.52 0.63 ;
    END
  END Q<1>
  PIN RSTB
    DIRECTION INOUT ;
    USE SIGNAL ;
    PORT
      LAYER METAL1 ;
        RECT 40.9 21.37 41.6 22.0 ;
    END
  END RSTB
  PIN Vd<3>
    DIRECTION INOUT ;
    USE SIGNAL ;
    PORT
      LAYER METAL1 ;
        RECT 0.0 3.3 0.42 4.0 ;
    END
  END Vd<3>
  PIN Vd<2>
    DIRECTION INOUT ;
    USE SIGNAL ;
    PORT
      LAYER METAL1 ;
        RECT 0.0 6.33 0.42 7.03 ;
    END
  END Vd<2>
  PIN Vd<1>
    DIRECTION INOUT ;
    USE SIGNAL ;
    PORT
      LAYER METAL1 ;
        RECT 0.0 14.5 0.42 15.2 ;
    END
  END Vd<1>
END Tgate_swc_fr_Kernel_Horiz_top_edge

MACRO Tgate_swc_fr_Kernel_Horiz_bot_edge
  PIN Q
    DIRECTION INOUT ;
    USE SIGNAL ;
    PORT
      LAYER METAL2 ;
        RECT 30.34 1.93 30.62 2.53 ;
    END
  END Q
  PIN GND
    DIRECTION INOUT ;
    USE SIGNAL ;
    PORT
      LAYER METAL1 ;
        RECT 30.84 21.37 31.64 22.0 ;
    END
  END GND
  PIN Final_row_out
    DIRECTION INOUT ;
    USE SIGNAL ;
    PORT
      LAYER METAL1 ;
        RECT 52.52 21.4 53.32 22.0 ;
    END
  END Final_row_out
  PIN I_m
    DIRECTION INOUT ;
    USE SIGNAL ;
    PORT
      LAYER METAL2 ;
        RECT 53.79 12.7 54.46 13.7 ;
    END
  END I_m
  PIN I_p
    DIRECTION INOUT ;
    USE SIGNAL ;
    PORT
      LAYER METAL2 ;
        RECT 53.79 16.27 54.46 17.27 ;
    END
  END I_p
  PIN Vd<0>
    DIRECTION INOUT ;
    USE SIGNAL ;
    PORT
      LAYER METAL1 ;
        RECT 0.0 17.5 0.42 18.2 ;
    END
  END Vd<0>
  PIN RUN_HV
    DIRECTION INOUT ;
    USE SIGNAL ;
    PORT
      LAYER METAL2 ;
        RECT 23.12 21.33 23.92 22.0 ;
    END
  END RUN_HV
  PIN VINJ
    DIRECTION INOUT ;
    USE SIGNAL ;
    PORT
      LAYER METAL2 ;
        RECT 9.08 21.33 10.08 22.0 ;
    END
  END VINJ
  PIN Vd_prog_0_out
    DIRECTION INOUT ;
    USE SIGNAL ;
    PORT
      LAYER METAL2 ;
        RECT 53.79 18.87 54.46 19.87 ;
    END
  END Vd_prog_0_out
  PIN Final_row_in
    DIRECTION INOUT ;
    USE SIGNAL ;
    PORT
      LAYER METAL1 ;
        RECT 52.52 0.86 53.32 1.46 ;
    END
  END Final_row_in
  PIN Vd_prog_0_in
    DIRECTION INOUT ;
    USE SIGNAL ;
    PORT
      LAYER METAL1 ;
        RECT 0.0 20.3 0.41 20.8 ;
    END
  END Vd_prog_0_in
  PIN DVDD
    DIRECTION INOUT ;
    USE SIGNAL ;
    PORT
      LAYER METAL1 ;
        RECT 43.41 21.37 44.11 22.0 ;
    END
  END DVDD
  PIN RSTB
    DIRECTION INOUT ;
    USE SIGNAL ;
    PORT
      LAYER METAL1 ;
        RECT 40.9 21.37 41.6 22.0 ;
    END
  END RSTB
  PIN CLK
    DIRECTION INOUT ;
    USE SIGNAL ;
    PORT
      LAYER METAL1 ;
        RECT 39.49 21.37 40.19 22.0 ;
    END
  END CLK
  PIN CLKB
    DIRECTION INOUT ;
    USE SIGNAL ;
    PORT
      LAYER METAL1 ;
        RECT 38.26 21.37 38.96 22.0 ;
    END
  END CLKB
  PIN Din
    DIRECTION INOUT ;
    USE SIGNAL ;
    PORT
      LAYER METAL1 ;
        RECT 49.82 21.37 50.52 22.0 ;
    END
  END Din
  PIN Vd<3>
    DIRECTION INOUT ;
    USE SIGNAL ;
    PORT
      LAYER METAL1 ;
        RECT 0.0 3.3 0.42 4.0 ;
    END
  END Vd<3>
  PIN Vd<2>
    DIRECTION INOUT ;
    USE SIGNAL ;
    PORT
      LAYER METAL1 ;
        RECT 0.0 6.33 0.42 7.03 ;
    END
  END Vd<2>
  PIN Vd<1>
    DIRECTION INOUT ;
    USE SIGNAL ;
    PORT
      LAYER METAL1 ;
        RECT 0.0 14.5 0.42 15.2 ;
    END
  END Vd<1>
END Tgate_swc_fr_Kernel_Horiz_bot_edge

MACRO AvgPool_n_Relu
  PIN DVDD
    DIRECTION INOUT ;
    USE SIGNAL ;
    PORT
      LAYER METAL2 ;
        RECT 94.23 9.83 94.6 10.63 ;
    END
  END DVDD
  PIN DVDD_l
    DIRECTION INOUT ;
    USE SIGNAL ;
    PORT
      LAYER METAL2 ;
        RECT 0.0 11.95 0.37 12.75 ;
    END
  END DVDD_l
  PIN Sub_img_out
    DIRECTION INOUT ;
    USE SIGNAL ;
    PORT
      LAYER METAL2 ;
        RECT 94.23 7.23 94.6 8.43 ;
    END
  END Sub_img_out
  PIN Out_En_b
    DIRECTION INOUT ;
    USE SIGNAL ;
    PORT
      LAYER METAL2 ;
        RECT 94.23 5.03 94.6 5.83 ;
    END
  END Out_En_b
  PIN Vd_prog_out
    DIRECTION INOUT ;
    USE SIGNAL ;
    PORT
      LAYER METAL2 ;
        RECT 94.23 19.8 94.6 20.6 ;
    END
  END Vd_prog_out
  PIN int_rst_out
    DIRECTION INOUT ;
    USE SIGNAL ;
    PORT
      LAYER METAL2 ;
        RECT 94.23 12.03 94.6 12.83 ;
    END
  END int_rst_out
  PIN Vint_out
    DIRECTION INOUT ;
    USE SIGNAL ;
    PORT
      LAYER METAL2 ;
        RECT 94.23 14.95 94.6 15.75 ;
    END
  END Vint_out
  PIN Q_out
    DIRECTION INOUT ;
    USE SIGNAL ;
    PORT
      LAYER METAL2 ;
        RECT 94.23 2.83 94.6 3.63 ;
    END
  END Q_out
  PIN GND
    DIRECTION INOUT ;
    USE SIGNAL ;
    PORT
      LAYER METAL2 ;
        RECT 94.23 17.15 94.6 18.35 ;
    END
  END GND
  PIN Q_in
    DIRECTION INOUT ;
    USE SIGNAL ;
    PORT
      LAYER METAL2 ;
        RECT 0.0 2.15 0.37 2.95 ;
    END
  END Q_in
  PIN Vint_in
    DIRECTION INOUT ;
    USE SIGNAL ;
    PORT
      LAYER METAL2 ;
        RECT 0.0 14.95 0.37 15.75 ;
    END
  END Vint_in
  PIN int_rst_in
    DIRECTION INOUT ;
    USE SIGNAL ;
    PORT
      LAYER METAL2 ;
        RECT 0.0 13.45 0.37 14.25 ;
    END
  END int_rst_in
  PIN Vd_prog_in
    DIRECTION INOUT ;
    USE SIGNAL ;
    PORT
      LAYER METAL2 ;
        RECT 0.0 20.43 0.37 21.23 ;
    END
  END Vd_prog_in
  PIN Vd_run
    DIRECTION INOUT ;
    USE SIGNAL ;
    PORT
      LAYER METAL2 ;
        RECT 0.0 16.45 0.37 17.25 ;
    END
  END Vd_run
  PIN AVDD
    DIRECTION INOUT ;
    USE SIGNAL ;
    PORT
      LAYER METAL1 ;
        RECT 80.32 21.53 81.32 22.0 ;
    END
  END AVDD
  PIN Vb
    DIRECTION INOUT ;
    USE SIGNAL ;
    PORT
      LAYER METAL1 ;
        RECT 52.1 21.53 53.1 22.0 ;
    END
  END Vb
  PIN run_lv
    DIRECTION INOUT ;
    USE SIGNAL ;
    PORT
      LAYER METAL1 ;
        RECT 8.03 21.53 9.03 22.0 ;
    END
  END run_lv
  PIN prog_lv
    DIRECTION INOUT ;
    USE SIGNAL ;
    PORT
      LAYER METAL1 ;
        RECT 5.63 21.53 6.63 22.0 ;
    END
  END prog_lv
END AvgPool_n_Relu

MACRO tile_analog_frame
  PIN n_Kvmm_G_En
    DIRECTION INOUT ;
    USE SIGNAL ;
    PORT
      LAYER METAL3 ;
        RECT 13.3 1702.21 14.7 1705.01 ;
    END
  END n_Kvmm_G_En
  PIN n_AvgPool_FGs_G_En
    DIRECTION INOUT ;
    USE SIGNAL ;
    PORT
      LAYER METAL3 ;
        RECT 27.3 1702.21 28.7 1705.01 ;
    END
  END n_AvgPool_FGs_G_En
  PIN n_Kvmm_G_bit<0>
    DIRECTION INOUT ;
    USE SIGNAL ;
    PORT
      LAYER METAL3 ;
        RECT 41.3 1702.21 42.7 1705.01 ;
    END
  END n_Kvmm_G_bit<0>
  PIN n_Kvmm_G_bit<1>
    DIRECTION INOUT ;
    USE SIGNAL ;
    PORT
      LAYER METAL3 ;
        RECT 55.3 1702.21 56.7 1705.01 ;
    END
  END n_Kvmm_G_bit<1>
  PIN n_Kvmm_G_bit<2>
    DIRECTION INOUT ;
    USE SIGNAL ;
    PORT
      LAYER METAL3 ;
        RECT 69.3 1702.21 70.7 1705.01 ;
    END
  END n_Kvmm_G_bit<2>
  PIN n_Kvmm_G_bit<3>
    DIRECTION INOUT ;
    USE SIGNAL ;
    PORT
      LAYER METAL3 ;
        RECT 83.3 1702.21 84.7 1705.01 ;
    END
  END n_Kvmm_G_bit<3>
  PIN n_Kvmm_AvgP_Dr_En
    DIRECTION INOUT ;
    USE SIGNAL ;
    PORT
      LAYER METAL3 ;
        RECT 97.3 1702.21 98.7 1705.01 ;
    END
  END n_Kvmm_AvgP_Dr_En
  PIN n_Kvmm_AvgP_Dr_bit<0>
    DIRECTION INOUT ;
    USE SIGNAL ;
    PORT
      LAYER METAL3 ;
        RECT 111.3 1702.21 112.7 1705.01 ;
    END
  END n_Kvmm_AvgP_Dr_bit<0>
  PIN n_Kvmm_AvgP_Dr_bit<1>
    DIRECTION INOUT ;
    USE SIGNAL ;
    PORT
      LAYER METAL3 ;
        RECT 125.3 1702.21 126.7 1705.01 ;
    END
  END n_Kvmm_AvgP_Dr_bit<1>
  PIN n_Kvmm_AvgP_Dr_bit<2>
    DIRECTION INOUT ;
    USE SIGNAL ;
    PORT
      LAYER METAL3 ;
        RECT 139.3 1702.21 140.7 1705.01 ;
    END
  END n_Kvmm_AvgP_Dr_bit<2>
  PIN n_Kvmm_AvgP_Dr_bit<3>
    DIRECTION INOUT ;
    USE SIGNAL ;
    PORT
      LAYER METAL3 ;
        RECT 153.3 1702.21 154.7 1705.01 ;
    END
  END n_Kvmm_AvgP_Dr_bit<3>
  PIN n_Kvmm_AvgP_Dr_bit<4>
    DIRECTION INOUT ;
    USE SIGNAL ;
    PORT
      LAYER METAL3 ;
        RECT 167.3 1702.21 168.7 1705.01 ;
    END
  END n_Kvmm_AvgP_Dr_bit<4>
  PIN n_Kvmm_AvgP_Dr_bit<5>
    DIRECTION INOUT ;
    USE SIGNAL ;
    PORT
      LAYER METAL3 ;
        RECT 181.3 1702.21 182.7 1705.01 ;
    END
  END n_Kvmm_AvgP_Dr_bit<5>
  PIN n_Kvmm_AvgP_Dr_bit<6>
    DIRECTION INOUT ;
    USE SIGNAL ;
    PORT
      LAYER METAL3 ;
        RECT 195.3 1702.21 196.7 1705.01 ;
    END
  END n_Kvmm_AvgP_Dr_bit<6>
  PIN n_Kvmm_AvgP_Dr_bit<7>
    DIRECTION INOUT ;
    USE SIGNAL ;
    PORT
      LAYER METAL3 ;
        RECT 209.3 1702.21 210.7 1705.01 ;
    END
  END n_Kvmm_AvgP_Dr_bit<7>
  PIN n_Kvmm_AvgP_Dr_bit<8>
    DIRECTION INOUT ;
    USE SIGNAL ;
    PORT
      LAYER METAL3 ;
        RECT 223.3 1702.21 224.7 1705.01 ;
    END
  END n_Kvmm_AvgP_Dr_bit<8>
  PIN n_Kvmm_AvgP_Prog_Drln
    DIRECTION INOUT ;
    USE SIGNAL ;
    PORT
      LAYER METAL3 ;
        RECT 237.3 1702.21 238.7 1705.01 ;
    END
  END n_Kvmm_AvgP_Prog_Drln
  PIN n_Kvmm_AvgP_Run_Drln
    DIRECTION INOUT ;
    USE SIGNAL ;
    PORT
      LAYER METAL3 ;
        RECT 251.3 1702.21 252.7 1705.01 ;
    END
  END n_Kvmm_AvgP_Run_Drln
  PIN n_K_col_Din
    DIRECTION INOUT ;
    USE SIGNAL ;
    PORT
      LAYER METAL3 ;
        RECT 265.3 1702.21 266.7 1705.01 ;
    END
  END n_K_col_Din
  PIN n_K_col_CLKB
    DIRECTION INOUT ;
    USE SIGNAL ;
    PORT
      LAYER METAL3 ;
        RECT 279.3 1702.21 280.7 1705.01 ;
    END
  END n_K_col_CLKB
  PIN n_K_col_RST_B
    DIRECTION INOUT ;
    USE SIGNAL ;
    PORT
      LAYER METAL3 ;
        RECT 293.3 1702.21 294.7 1705.01 ;
    END
  END n_K_col_RST_B
  PIN n_K_col_CLK
    DIRECTION INOUT ;
    USE SIGNAL ;
    PORT
      LAYER METAL3 ;
        RECT 307.3 1702.21 308.7 1705.01 ;
    END
  END n_K_col_CLK
  PIN n_AVDD_by_2
    DIRECTION INOUT ;
    USE SIGNAL ;
    PORT
      LAYER METAL3 ;
        RECT 321.3 1702.21 322.7 1705.01 ;
    END
  END n_AVDD_by_2
  PIN n_SR_Intg_RST_B
    DIRECTION INOUT ;
    USE SIGNAL ;
    PORT
      LAYER METAL3 ;
        RECT 335.3 1702.21 336.7 1705.01 ;
    END
  END n_SR_Intg_RST_B
  PIN n_SR_Intg_Din
    DIRECTION INOUT ;
    USE SIGNAL ;
    PORT
      LAYER METAL3 ;
        RECT 349.3 1702.21 350.7 1705.01 ;
    END
  END n_SR_Intg_Din
  PIN n_SR_Intg_CLK
    DIRECTION INOUT ;
    USE SIGNAL ;
    PORT
      LAYER METAL3 ;
        RECT 363.3 1702.21 364.7 1705.01 ;
    END
  END n_SR_Intg_CLK
  PIN n_SR_Intg_CLKB
    DIRECTION INOUT ;
    USE SIGNAL ;
    PORT
      LAYER METAL3 ;
        RECT 377.3 1702.21 378.7 1705.01 ;
    END
  END n_SR_Intg_CLKB
  PIN n_SR_Intg_nxt_rw
    DIRECTION INOUT ;
    USE SIGNAL ;
    PORT
      LAYER METAL3 ;
        RECT 391.3 1702.21 392.7 1705.01 ;
    END
  END n_SR_Intg_nxt_rw
  PIN n_Vimg_CLK
    DIRECTION INOUT ;
    USE SIGNAL ;
    PORT
      LAYER METAL3 ;
        RECT 405.3 1702.21 406.7 1705.01 ;
    END
  END n_Vimg_CLK
  PIN n_K_rw_Din
    DIRECTION INOUT ;
    USE SIGNAL ;
    PORT
      LAYER METAL3 ;
        RECT 419.3 1702.21 420.7 1705.01 ;
    END
  END n_K_rw_Din
  PIN n_K_rw_CLKB
    DIRECTION INOUT ;
    USE SIGNAL ;
    PORT
      LAYER METAL3 ;
        RECT 433.3 1702.21 434.7 1705.01 ;
    END
  END n_K_rw_CLKB
  PIN n_K_rw_RST_B
    DIRECTION INOUT ;
    USE SIGNAL ;
    PORT
      LAYER METAL3 ;
        RECT 447.3 1702.21 448.7 1705.01 ;
    END
  END n_K_rw_RST_B
  PIN n_K_rw_CLK
    DIRECTION INOUT ;
    USE SIGNAL ;
    PORT
      LAYER METAL3 ;
        RECT 461.3 1702.21 462.7 1705.01 ;
    END
  END n_K_rw_CLK
  PIN n_AvgPool_Relu_Vb
    DIRECTION INOUT ;
    USE SIGNAL ;
    PORT
      LAYER METAL3 ;
        RECT 475.3 1702.21 476.7 1705.01 ;
    END
  END n_AvgPool_Relu_Vb
  PIN n_VTUN
    DIRECTION INOUT ;
    USE SIGNAL ;
    PORT
      LAYER METAL3 ;
        RECT 489.3 1702.21 490.7 1705.01 ;
    END
  END n_VTUN
  PIN n_DVDD
    DIRECTION INOUT ;
    USE SIGNAL ;
    PORT
      LAYER METAL3 ;
        RECT 503.3 1702.21 504.7 1705.01 ;
    END
  END n_DVDD
  PIN n_AVDD
    DIRECTION INOUT ;
    USE SIGNAL ;
    PORT
      LAYER METAL3 ;
        RECT 517.3 1702.21 518.7 1705.01 ;
    END
  END n_AVDD
  PIN n_GND
    DIRECTION INOUT ;
    USE SIGNAL ;
    PORT
      LAYER METAL3 ;
        RECT 531.3 1702.21 532.7 1705.01 ;
    END
  END n_GND
  PIN n_VINJ
    DIRECTION INOUT ;
    USE SIGNAL ;
    PORT
      LAYER METAL3 ;
        RECT 545.3 1702.21 546.7 1705.01 ;
    END
  END n_VINJ
  PIN n_VGPROG
    DIRECTION INOUT ;
    USE SIGNAL ;
    PORT
      LAYER METAL3 ;
        RECT 559.3 1702.21 560.7 1705.01 ;
    END
  END n_VGPROG
  PIN n_prog_hv
    DIRECTION INOUT ;
    USE SIGNAL ;
    PORT
      LAYER METAL3 ;
        RECT 573.3 1702.21 574.7 1705.01 ;
    END
  END n_prog_hv
  PIN n_run_hv
    DIRECTION INOUT ;
    USE SIGNAL ;
    PORT
      LAYER METAL3 ;
        RECT 587.3 1702.21 588.7 1705.01 ;
    END
  END n_run_hv
  PIN n_prog_lv
    DIRECTION INOUT ;
    USE SIGNAL ;
    PORT
      LAYER METAL3 ;
        RECT 601.3 1702.21 602.7 1705.01 ;
    END
  END n_prog_lv
  PIN n_run_lv
    DIRECTION INOUT ;
    USE SIGNAL ;
    PORT
      LAYER METAL3 ;
        RECT 615.3 1702.21 616.7 1705.01 ;
    END
  END n_run_lv
  PIN e_Vin_inp_Ch<0>
    DIRECTION INOUT ;
    USE SIGNAL ;
    PORT
      LAYER METAL3 ;
        RECT 1812.51 1689.61 1815.31 1691.01 ;
    END
  END e_Vin_inp_Ch<0>
  PIN e_Vin_inp_Ch<1>
    DIRECTION INOUT ;
    USE SIGNAL ;
    PORT
      LAYER METAL3 ;
        RECT 1812.51 1675.61 1815.31 1677.01 ;
    END
  END e_Vin_inp_Ch<1>
  PIN e_Vin_inp_Ch<2>
    DIRECTION INOUT ;
    USE SIGNAL ;
    PORT
      LAYER METAL3 ;
        RECT 1812.51 1661.61 1815.31 1663.01 ;
    END
  END e_Vin_inp_Ch<2>
  PIN e_Sub_img_out<0>
    DIRECTION INOUT ;
    USE SIGNAL ;
    PORT
      LAYER METAL3 ;
        RECT 1812.51 1647.61 1815.31 1649.01 ;
    END
  END e_Sub_img_out<0>
  PIN e_Sub_img_out<1>
    DIRECTION INOUT ;
    USE SIGNAL ;
    PORT
      LAYER METAL3 ;
        RECT 1812.51 1633.61 1815.31 1635.01 ;
    END
  END e_Sub_img_out<1>
  PIN e_Sub_img_out<2>
    DIRECTION INOUT ;
    USE SIGNAL ;
    PORT
      LAYER METAL3 ;
        RECT 1812.51 1619.61 1815.31 1621.01 ;
    END
  END e_Sub_img_out<2>
  PIN e_Sub_img_out<3>
    DIRECTION INOUT ;
    USE SIGNAL ;
    PORT
      LAYER METAL3 ;
        RECT 1812.51 1605.61 1815.31 1607.01 ;
    END
  END e_Sub_img_out<3>
  PIN e_Sub_img_out<4>
    DIRECTION INOUT ;
    USE SIGNAL ;
    PORT
      LAYER METAL3 ;
        RECT 1812.51 1591.61 1815.31 1593.01 ;
    END
  END e_Sub_img_out<4>
  PIN e_Sub_img_out<5>
    DIRECTION INOUT ;
    USE SIGNAL ;
    PORT
      LAYER METAL3 ;
        RECT 1812.51 1577.61 1815.31 1579.01 ;
    END
  END e_Sub_img_out<5>
  PIN e_Sub_img_out<6>
    DIRECTION INOUT ;
    USE SIGNAL ;
    PORT
      LAYER METAL3 ;
        RECT 1812.51 1563.61 1815.31 1565.01 ;
    END
  END e_Sub_img_out<6>
  PIN e_Sub_img_out<7>
    DIRECTION INOUT ;
    USE SIGNAL ;
    PORT
      LAYER METAL3 ;
        RECT 1812.51 1549.61 1815.31 1551.01 ;
    END
  END e_Sub_img_out<7>
  PIN e_Sub_img_out<8>
    DIRECTION INOUT ;
    USE SIGNAL ;
    PORT
      LAYER METAL3 ;
        RECT 1812.51 1535.61 1815.31 1537.01 ;
    END
  END e_Sub_img_out<8>
  PIN e_Sub_img_out<9>
    DIRECTION INOUT ;
    USE SIGNAL ;
    PORT
      LAYER METAL3 ;
        RECT 1812.51 1521.61 1815.31 1523.01 ;
    END
  END e_Sub_img_out<9>
  PIN e_Sub_img_out<10>
    DIRECTION INOUT ;
    USE SIGNAL ;
    PORT
      LAYER METAL3 ;
        RECT 1812.51 1507.61 1815.31 1509.01 ;
    END
  END e_Sub_img_out<10>
  PIN e_Sub_img_out<11>
    DIRECTION INOUT ;
    USE SIGNAL ;
    PORT
      LAYER METAL3 ;
        RECT 1812.51 1493.61 1815.31 1495.01 ;
    END
  END e_Sub_img_out<11>
  PIN e_Sub_img_out<12>
    DIRECTION INOUT ;
    USE SIGNAL ;
    PORT
      LAYER METAL3 ;
        RECT 1812.51 1479.61 1815.31 1481.01 ;
    END
  END e_Sub_img_out<12>
  PIN e_Sub_img_out<13>
    DIRECTION INOUT ;
    USE SIGNAL ;
    PORT
      LAYER METAL3 ;
        RECT 1812.51 1465.61 1815.31 1467.01 ;
    END
  END e_Sub_img_out<13>
  PIN e_Sub_img_out<14>
    DIRECTION INOUT ;
    USE SIGNAL ;
    PORT
      LAYER METAL3 ;
        RECT 1812.51 1451.61 1815.31 1453.01 ;
    END
  END e_Sub_img_out<14>
  PIN e_Sub_img_out<15>
    DIRECTION INOUT ;
    USE SIGNAL ;
    PORT
      LAYER METAL3 ;
        RECT 1812.51 1437.61 1815.31 1439.01 ;
    END
  END e_Sub_img_out<15>
  PIN e_Sub_img_out<16>
    DIRECTION INOUT ;
    USE SIGNAL ;
    PORT
      LAYER METAL3 ;
        RECT 1812.51 1423.61 1815.31 1425.01 ;
    END
  END e_Sub_img_out<16>
  PIN e_Sub_img_out<17>
    DIRECTION INOUT ;
    USE SIGNAL ;
    PORT
      LAYER METAL3 ;
        RECT 1812.51 1409.61 1815.31 1411.01 ;
    END
  END e_Sub_img_out<17>
  PIN e_Sub_img_out<18>
    DIRECTION INOUT ;
    USE SIGNAL ;
    PORT
      LAYER METAL3 ;
        RECT 1812.51 1395.61 1815.31 1397.01 ;
    END
  END e_Sub_img_out<18>
  PIN e_Sub_img_out<19>
    DIRECTION INOUT ;
    USE SIGNAL ;
    PORT
      LAYER METAL3 ;
        RECT 1812.51 1381.61 1815.31 1383.01 ;
    END
  END e_Sub_img_out<19>
  PIN e_Sub_img_out<20>
    DIRECTION INOUT ;
    USE SIGNAL ;
    PORT
      LAYER METAL3 ;
        RECT 1812.51 1367.61 1815.31 1369.01 ;
    END
  END e_Sub_img_out<20>
  PIN e_Sub_img_out<21>
    DIRECTION INOUT ;
    USE SIGNAL ;
    PORT
      LAYER METAL3 ;
        RECT 1812.51 1353.61 1815.31 1355.01 ;
    END
  END e_Sub_img_out<21>
  PIN e_Sub_img_out<22>
    DIRECTION INOUT ;
    USE SIGNAL ;
    PORT
      LAYER METAL3 ;
        RECT 1812.51 1339.61 1815.31 1341.01 ;
    END
  END e_Sub_img_out<22>
  PIN e_Sub_img_out<23>
    DIRECTION INOUT ;
    USE SIGNAL ;
    PORT
      LAYER METAL3 ;
        RECT 1812.51 1325.61 1815.31 1327.01 ;
    END
  END e_Sub_img_out<23>
  PIN e_Sub_img_out<24>
    DIRECTION INOUT ;
    USE SIGNAL ;
    PORT
      LAYER METAL3 ;
        RECT 1812.51 1311.61 1815.31 1313.01 ;
    END
  END e_Sub_img_out<24>
  PIN e_Sub_img_out<25>
    DIRECTION INOUT ;
    USE SIGNAL ;
    PORT
      LAYER METAL3 ;
        RECT 1812.51 1297.61 1815.31 1299.01 ;
    END
  END e_Sub_img_out<25>
  PIN e_Sub_img_out<26>
    DIRECTION INOUT ;
    USE SIGNAL ;
    PORT
      LAYER METAL3 ;
        RECT 1812.51 1283.61 1815.31 1285.01 ;
    END
  END e_Sub_img_out<26>
  PIN e_Sub_img_out<27>
    DIRECTION INOUT ;
    USE SIGNAL ;
    PORT
      LAYER METAL3 ;
        RECT 1812.51 1269.61 1815.31 1271.01 ;
    END
  END e_Sub_img_out<27>
  PIN e_Sub_img_out<28>
    DIRECTION INOUT ;
    USE SIGNAL ;
    PORT
      LAYER METAL3 ;
        RECT 1812.51 1255.61 1815.31 1257.01 ;
    END
  END e_Sub_img_out<28>
  PIN e_Sub_img_out<29>
    DIRECTION INOUT ;
    USE SIGNAL ;
    PORT
      LAYER METAL3 ;
        RECT 1812.51 1241.61 1815.31 1243.01 ;
    END
  END e_Sub_img_out<29>
  PIN e_Sub_img_out<30>
    DIRECTION INOUT ;
    USE SIGNAL ;
    PORT
      LAYER METAL3 ;
        RECT 1812.51 1227.61 1815.31 1229.01 ;
    END
  END e_Sub_img_out<30>
  PIN e_Sub_img_out<31>
    DIRECTION INOUT ;
    USE SIGNAL ;
    PORT
      LAYER METAL3 ;
        RECT 1812.51 1213.61 1815.31 1215.01 ;
    END
  END e_Sub_img_out<31>
  PIN e_Sub_img_out<32>
    DIRECTION INOUT ;
    USE SIGNAL ;
    PORT
      LAYER METAL3 ;
        RECT 1812.51 1199.61 1815.31 1201.01 ;
    END
  END e_Sub_img_out<32>
  PIN e_Sub_img_out<33>
    DIRECTION INOUT ;
    USE SIGNAL ;
    PORT
      LAYER METAL3 ;
        RECT 1812.51 1185.61 1815.31 1187.01 ;
    END
  END e_Sub_img_out<33>
END tile_analog_frame

MACRO TSMC350nm_4x2_Indirect
  PIN Vg<1>
    DIRECTION INOUT ;
    USE SIGNAL ;
    PORT
      LAYER METAL2 ;
        RECT 18.2 21.06 18.8 22.0 ;
    END
  END Vg<1>
  PIN Vsel<1>
    DIRECTION INOUT ;
    USE SIGNAL ;
    PORT
      LAYER METAL2 ;
        RECT 20.3 21.08 20.9 22.0 ;
    END
  END Vsel<1>
  PIN VINJ<1>
    DIRECTION INOUT ;
    USE SIGNAL ;
    PORT
      LAYER METAL2 ;
        RECT 22.4 21.05 23.0 22.0 ;
    END
  END VINJ<1>
  PIN Vsel<0>
    DIRECTION INOUT ;
    USE SIGNAL ;
    PORT
      LAYER METAL2 ;
        RECT 6.3 21.2 6.9 22.0 ;
    END
  END Vsel<0>
  PIN Vs<0>
    DIRECTION INOUT ;
    USE SIGNAL ;
    PORT
      LAYER METAL2 ;
        RECT 2.1 21.21 2.7 22.0 ;
    END
  END Vs<0>
  PIN Vs<1>
    DIRECTION INOUT ;
    USE SIGNAL ;
    PORT
      LAYER METAL2 ;
        RECT 24.5 21.06 25.1 22.0 ;
    END
  END Vs<1>
  PIN VTUN
    DIRECTION INOUT ;
    USE SIGNAL ;
    PORT
      LAYER METAL2 ;
        RECT 13.3 21.09 13.9 22.0 ;
    END
  END VTUN
  PIN VINJ<0>
    DIRECTION INOUT ;
    USE SIGNAL ;
    PORT
      LAYER METAL2 ;
        RECT 4.2 21.18 4.8 22.0 ;
    END
  END VINJ<0>
  PIN GND<0>
    DIRECTION INOUT ;
    USE SIGNAL ;
    PORT
      LAYER METAL2 ;
        RECT 11.2 21.07 11.8 22.0 ;
    END
  END GND<0>
  PIN Vg<0>
    DIRECTION INOUT ;
    USE SIGNAL ;
    PORT
      LAYER METAL2 ;
        RECT 8.4 21.03 9.0 22.0 ;
    END
  END Vg<0>
  PIN GND<1>
    DIRECTION INOUT ;
    USE SIGNAL ;
    PORT
      LAYER METAL2 ;
        RECT 15.41 21.06 16.01 22.0 ;
    END
  END GND<1>
  PIN Vs_b<0>
    DIRECTION INOUT ;
    USE SIGNAL ;
    PORT
      LAYER METAL2 ;
        RECT 1.42 0.0 2.7 0.6 ;
    END
  END Vs_b<0>
  PIN VINJ_b<0>
    DIRECTION INOUT ;
    USE SIGNAL ;
    PORT
      LAYER METAL2 ;
        RECT 4.2 0.0 4.8 0.76 ;
    END
  END VINJ_b<0>
  PIN Vsel_b<0>
    DIRECTION INOUT ;
    USE SIGNAL ;
    PORT
      LAYER METAL2 ;
        RECT 6.3 0.0 6.9 0.78 ;
    END
  END Vsel_b<0>
  PIN Vg_b<0>
    DIRECTION INOUT ;
    USE SIGNAL ;
    PORT
      LAYER METAL2 ;
        RECT 8.4 0.0 9.0 0.77 ;
    END
  END Vg_b<0>
  PIN GND_b<0>
    DIRECTION INOUT ;
    USE SIGNAL ;
    PORT
      LAYER METAL2 ;
        RECT 11.2 0.0 11.8 0.76 ;
    END
  END GND_b<0>
  PIN VTUN_b
    DIRECTION INOUT ;
    USE SIGNAL ;
    PORT
      LAYER METAL2 ;
        RECT 13.3 0.0 13.9 0.76 ;
    END
  END VTUN_b
  PIN GND_b<1>
    DIRECTION INOUT ;
    USE SIGNAL ;
    PORT
      LAYER METAL2 ;
        RECT 15.41 0.0 16.01 0.83 ;
    END
  END GND_b<1>
  PIN Vg_b<1>
    DIRECTION INOUT ;
    USE SIGNAL ;
    PORT
      LAYER METAL2 ;
        RECT 18.2 0.0 18.8 0.76 ;
    END
  END Vg_b<1>
  PIN Vsel_b<1>
    DIRECTION INOUT ;
    USE SIGNAL ;
    PORT
      LAYER METAL2 ;
        RECT 20.3 0.0 20.9 0.75 ;
    END
  END Vsel_b<1>
  PIN VINJ_b<1>
    DIRECTION INOUT ;
    USE SIGNAL ;
    PORT
      LAYER METAL2 ;
        RECT 22.4 0.0 23.0 0.77 ;
    END
  END VINJ_b<1>
  PIN Vs_b<1>
    DIRECTION INOUT ;
    USE SIGNAL ;
    PORT
      LAYER METAL2 ;
        RECT 24.5 0.0 25.75 0.61 ;
    END
  END Vs_b<1>
  PIN Vd_Pl<3>
    DIRECTION INOUT ;
    USE SIGNAL ;
    PORT
      LAYER METAL1 ;
        RECT 0.0 0.7 1.47 1.2 ;
    END
  END Vd_Pl<3>
  PIN Vd_Rl<3>
    DIRECTION INOUT ;
    USE SIGNAL ;
    PORT
      LAYER METAL1 ;
        RECT 0.0 3.5 1.45 4.0 ;
    END
  END Vd_Rl<3>
  PIN Vd_Rl<2>
    DIRECTION INOUT ;
    USE SIGNAL ;
    PORT
      LAYER METAL1 ;
        RECT 0.0 7.0 1.4 7.5 ;
    END
  END Vd_Rl<2>
  PIN Vd_Pl<2>
    DIRECTION INOUT ;
    USE SIGNAL ;
    PORT
      LAYER METAL1 ;
        RECT 0.0 9.8 1.41 10.3 ;
    END
  END Vd_Pl<2>
  PIN Vd_Pl<1>
    DIRECTION INOUT ;
    USE SIGNAL ;
    PORT
      LAYER METAL1 ;
        RECT 0.0 11.89 1.43 12.4 ;
    END
  END Vd_Pl<1>
  PIN Vd_Rl<1>
    DIRECTION INOUT ;
    USE SIGNAL ;
    PORT
      LAYER METAL1 ;
        RECT 0.0 14.7 1.46 15.2 ;
    END
  END Vd_Rl<1>
  PIN Vd_Rl<0>
    DIRECTION INOUT ;
    USE SIGNAL ;
    PORT
      LAYER METAL1 ;
        RECT 0.0 17.5 1.43 18.0 ;
    END
  END Vd_Rl<0>
  PIN Vd_Pl<0>
    DIRECTION INOUT ;
    USE SIGNAL ;
    PORT
      LAYER METAL1 ;
        RECT 0.0 20.3 1.4 20.9 ;
    END
  END Vd_Pl<0>
  PIN Vd_P<0>
    DIRECTION INOUT ;
    USE SIGNAL ;
    PORT
      LAYER METAL1 ;
        RECT 26.63 20.3 27.46 20.8 ;
    END
  END Vd_P<0>
  PIN Vd_R<1>
    DIRECTION INOUT ;
    USE SIGNAL ;
    PORT
      LAYER METAL1 ;
        RECT 26.56 14.7 27.44 15.2 ;
    END
  END Vd_R<1>
  PIN Vd_R<3>
    DIRECTION INOUT ;
    USE SIGNAL ;
    PORT
      LAYER METAL1 ;
        RECT 26.5 3.5 27.46 4.0 ;
    END
  END Vd_R<3>
  PIN Vd_P<3>
    DIRECTION INOUT ;
    USE SIGNAL ;
    PORT
      LAYER METAL1 ;
        RECT 26.55 0.7 27.46 1.2 ;
    END
  END Vd_P<3>
  PIN Vd_P<1>
    DIRECTION INOUT ;
    USE SIGNAL ;
    PORT
      LAYER METAL1 ;
        RECT 26.38 11.9 27.46 12.4 ;
    END
  END Vd_P<1>
  PIN Vd_P<2>
    DIRECTION INOUT ;
    USE SIGNAL ;
    PORT
      LAYER METAL1 ;
        RECT 26.51 9.8 27.46 10.3 ;
    END
  END Vd_P<2>
  PIN Vd_R<0>
    DIRECTION INOUT ;
    USE SIGNAL ;
    PORT
      LAYER METAL1 ;
        RECT 26.66 17.5 27.46 18.0 ;
    END
  END Vd_R<0>
  PIN Vd_R<2>
    DIRECTION INOUT ;
    USE SIGNAL ;
    PORT
      LAYER METAL1 ;
        RECT 26.53 7.0 27.46 7.5 ;
    END
  END Vd_R<2>
END TSMC350nm_4x2_Indirect

MACRO Integration_fr_AvgPool_start
  PIN GND
    DIRECTION INOUT ;
    USE SIGNAL ;
    PORT
      LAYER METAL1 ;
        RECT 71.84 21.51 73.23 22.0 ;
    END
  END GND
  PIN Q
    DIRECTION INOUT ;
    USE SIGNAL ;
    PORT
      LAYER METAL3 ;
        RECT 0.0 6.24 0.6 7.04 ;
    END
  END Q
  PIN Vd_run
    DIRECTION INOUT ;
    USE SIGNAL ;
    PORT
      LAYER METAL2 ;
        RECT 0.0 16.45 0.37 17.25 ;
    END
  END Vd_run
  PIN Vd_prog
    DIRECTION INOUT ;
    USE SIGNAL ;
    PORT
      LAYER METAL2 ;
        RECT 0.0 20.43 0.37 21.23 ;
    END
  END Vd_prog
  PIN int_rst
    DIRECTION INOUT ;
    USE SIGNAL ;
    PORT
      LAYER METAL2 ;
        RECT 0.0 13.45 0.37 14.25 ;
    END
  END int_rst
  PIN Vint
    DIRECTION INOUT ;
    USE SIGNAL ;
    PORT
      LAYER METAL2 ;
        RECT 0.0 14.95 0.37 15.75 ;
    END
  END Vint
  PIN DVDD
    DIRECTION INOUT ;
    USE SIGNAL ;
    PORT
      LAYER METAL2 ;
        RECT 0.0 11.95 0.37 12.75 ;
    END
  END DVDD
  PIN Din
    DIRECTION INOUT ;
    USE SIGNAL ;
    PORT
      LAYER METAL3 ;
        RECT 0.0 2.15 0.6 2.95 ;
    END
  END Din
  PIN RST_B
    DIRECTION INOUT ;
    USE SIGNAL ;
    PORT
      LAYER METAL1 ;
        RECT 14.55 21.51 15.35 22.0 ;
    END
  END RST_B
  PIN CLK
    DIRECTION INOUT ;
    USE SIGNAL ;
    PORT
      LAYER METAL1 ;
        RECT 13.14 21.51 14.1 22.0 ;
    END
  END CLK
  PIN Vimg_CLK
    DIRECTION INOUT ;
    USE SIGNAL ;
    PORT
      LAYER METAL1 ;
        RECT 27.28 21.51 28.28 22.0 ;
    END
  END Vimg_CLK
  PIN CLKB
    DIRECTION INOUT ;
    USE SIGNAL ;
    PORT
      LAYER METAL1 ;
        RECT 11.61 21.51 12.61 22.0 ;
    END
  END CLKB
  PIN nxt_rw<1>
    DIRECTION INOUT ;
    USE SIGNAL ;
    PORT
      LAYER METAL1 ;
        RECT 290.26 21.52 291.26 22.0 ;
    END
  END nxt_rw<1>
  PIN AVDD_by_2<1>
    DIRECTION INOUT ;
    USE SIGNAL ;
    PORT
      LAYER METAL1 ;
        RECT 197.65 21.52 198.65 22.0 ;
    END
  END AVDD_by_2<1>
  PIN prog<1>
    DIRECTION INOUT ;
    USE SIGNAL ;
    PORT
      LAYER METAL1 ;
        RECT 195.23 21.52 196.23 22.0 ;
    END
  END prog<1>
  PIN run<1>
    DIRECTION INOUT ;
    USE SIGNAL ;
    PORT
      LAYER METAL1 ;
        RECT 192.83 21.52 193.83 22.0 ;
    END
  END run<1>
  PIN Vg<1>
    DIRECTION INOUT ;
    USE SIGNAL ;
    PORT
      LAYER METAL1 ;
        RECT 190.43 21.52 191.43 22.0 ;
    END
  END Vg<1>
  PIN Vsel_b<1>
    DIRECTION INOUT ;
    USE SIGNAL ;
    PORT
      LAYER METAL1 ;
        RECT 187.93 21.51 188.93 22.0 ;
    END
  END Vsel_b<1>
  PIN AVDD<1>
    DIRECTION INOUT ;
    USE SIGNAL ;
    PORT
      LAYER METAL1 ;
        RECT 185.43 21.51 186.43 22.0 ;
    END
  END AVDD<1>
  PIN VINJ<1>
    DIRECTION INOUT ;
    USE SIGNAL ;
    PORT
      LAYER METAL1 ;
        RECT 176.82 21.51 177.82 22.0 ;
    END
  END VINJ<1>
  PIN VTUN
    DIRECTION INOUT ;
    USE SIGNAL ;
    PORT
      LAYER METAL1 ;
        RECT 167.86 21.51 168.86 22.0 ;
    END
  END VTUN
  PIN VINJ<0>
    DIRECTION INOUT ;
    USE SIGNAL ;
    PORT
      LAYER METAL1 ;
        RECT 158.92 21.51 159.92 22.0 ;
    END
  END VINJ<0>
  PIN AVDD<0>
    DIRECTION INOUT ;
    USE SIGNAL ;
    PORT
      LAYER METAL1 ;
        RECT 150.82 21.51 151.82 22.0 ;
    END
  END AVDD<0>
  PIN Vsel_b<0>
    DIRECTION INOUT ;
    USE SIGNAL ;
    PORT
      LAYER METAL1 ;
        RECT 148.32 21.51 149.32 22.0 ;
    END
  END Vsel_b<0>
  PIN Vg<0>
    DIRECTION INOUT ;
    USE SIGNAL ;
    PORT
      LAYER METAL1 ;
        RECT 145.82 21.51 146.82 22.0 ;
    END
  END Vg<0>
  PIN run<0>
    DIRECTION INOUT ;
    USE SIGNAL ;
    PORT
      LAYER METAL1 ;
        RECT 143.42 21.51 144.42 22.0 ;
    END
  END run<0>
  PIN prog<0>
    DIRECTION INOUT ;
    USE SIGNAL ;
    PORT
      LAYER METAL1 ;
        RECT 141.02 21.51 142.02 22.0 ;
    END
  END prog<0>
  PIN AVDD_by_2<0>
    DIRECTION INOUT ;
    USE SIGNAL ;
    PORT
      LAYER METAL1 ;
        RECT 138.6 21.51 139.6 22.0 ;
    END
  END AVDD_by_2<0>
  PIN nxt_rw<0>
    DIRECTION INOUT ;
    USE SIGNAL ;
    PORT
      LAYER METAL1 ;
        RECT 45.99 21.51 46.99 22.0 ;
    END
  END nxt_rw<0>
END Integration_fr_AvgPool_start

MACRO I_Subtractor_AvgPool_top
  PIN I_m
    DIRECTION INOUT ;
    USE SIGNAL ;
    PORT
      LAYER METAL2 ;
        RECT 0.0 12.7 0.37 13.7 ;
    END
  END I_m
  PIN Vd_prog_0_in
    DIRECTION INOUT ;
    USE SIGNAL ;
    PORT
      LAYER METAL2 ;
        RECT 0.0 18.88 0.37 19.88 ;
    END
  END Vd_prog_0_in
  PIN Vd_prog_0_out
    DIRECTION INOUT ;
    USE SIGNAL ;
    PORT
      LAYER METAL2 ;
        RECT 38.54 20.43 38.91 21.23 ;
    END
  END Vd_prog_0_out
  PIN Vd_run_krnl
    DIRECTION INOUT ;
    USE SIGNAL ;
    PORT
      LAYER METAL2 ;
        RECT 0.0 5.66 0.37 6.66 ;
    END
  END Vd_run_krnl
  PIN Vd_run_avg_pool
    DIRECTION INOUT ;
    USE SIGNAL ;
    PORT
      LAYER METAL2 ;
        RECT 38.54 16.45 38.91 17.25 ;
    END
  END Vd_run_avg_pool
  PIN Vint
    DIRECTION INOUT ;
    USE SIGNAL ;
    PORT
      LAYER METAL2 ;
        RECT 0.0 16.27 0.37 17.27 ;
    END
  END Vint
  PIN DVDD
    DIRECTION INOUT ;
    USE SIGNAL ;
    PORT
      LAYER METAL1 ;
        RECT 31.8 21.54 32.8 22.0 ;
    END
  END DVDD
  PIN GND
    DIRECTION INOUT ;
    USE SIGNAL ;
    PORT
      LAYER METAL1 ;
        RECT 12.02 21.54 17.24 22.0 ;
    END
  END GND
  PIN run_lv
    DIRECTION INOUT ;
    USE SIGNAL ;
    PORT
      LAYER METAL1 ;
        RECT 36.65 21.54 37.65 22.0 ;
    END
  END run_lv
  PIN prog_lv
    DIRECTION INOUT ;
    USE SIGNAL ;
    PORT
      LAYER METAL1 ;
        RECT 29.8 21.54 30.8 22.0 ;
    END
  END prog_lv
END I_Subtractor_AvgPool_top

MACRO FakeCellGateDecoder
END FakeCellGateDecoder

END LIBRARY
